VERSION 5.7 ;
  NOWIREEXTENSIONATPIN ON ;
  DIVIDERCHAR "/" ;
  BUSBITCHARS "[]" ;
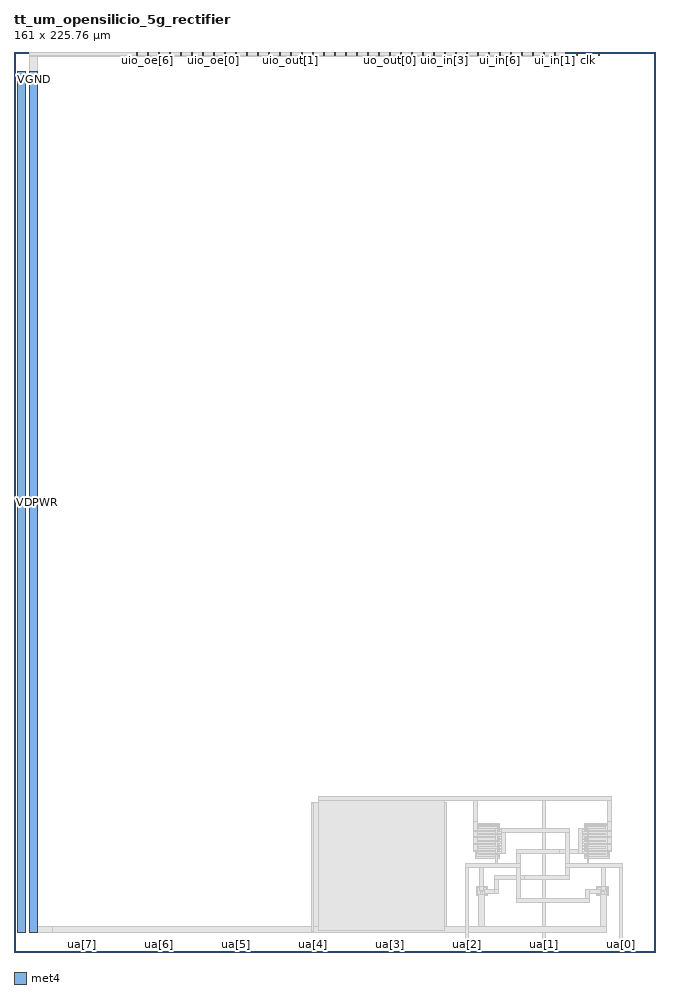
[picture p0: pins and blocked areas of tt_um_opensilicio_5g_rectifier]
MACRO tt_um_opensilicio_5g_rectifier
  CLASS BLOCK ;
  FOREIGN tt_um_opensilicio_5g_rectifier ;
  ORIGIN 0.000 0.000 ;
  SIZE 161.000 BY 225.760 ;
  PIN clk
    PORT
      LAYER met4 ;
        RECT 143.830 224.760 144.130 225.760 ;
    END
  END clk
  PIN ena
    PORT
      LAYER met4 ;
        RECT 146.590 224.760 146.890 225.760 ;
    END
  END ena
  PIN rst_n
    PORT
      LAYER met4 ;
        RECT 141.070 224.760 141.370 225.760 ;
    END
  END rst_n
  PIN ua[0]
    ANTENNAGATEAREA 11.349999 ;
    ANTENNADIFFAREA 8.700000 ;
    PORT
      LAYER met4 ;
        RECT 151.810 0.000 152.710 1.000 ;
    END
  END ua[0]
  PIN ua[1]
    ANTENNADIFFAREA 25.118799 ;
    PORT
      LAYER met4 ;
        RECT 132.490 0.000 133.390 1.000 ;
    END
  END ua[1]
  PIN ua[2]
    ANTENNAGATEAREA 11.349999 ;
    ANTENNADIFFAREA 8.700000 ;
    PORT
      LAYER met4 ;
        RECT 113.170 0.000 114.070 1.000 ;
    END
  END ua[2]
  PIN ua[3]
    PORT
      LAYER met4 ;
        RECT 93.850 0.000 94.750 1.000 ;
    END
  END ua[3]
  PIN ua[4]
    PORT
      LAYER met4 ;
        RECT 74.530 0.000 75.430 1.000 ;
    END
  END ua[4]
  PIN ua[5]
    PORT
      LAYER met4 ;
        RECT 55.210 0.000 56.110 1.000 ;
    END
  END ua[5]
  PIN ua[6]
    PORT
      LAYER met4 ;
        RECT 35.890 0.000 36.790 1.000 ;
    END
  END ua[6]
  PIN ua[7]
    PORT
      LAYER met4 ;
        RECT 16.570 0.000 17.470 1.000 ;
    END
  END ua[7]
  PIN ui_in[0]
    ANTENNADIFFAREA 3.496800 ;
    PORT
      LAYER met4 ;
        RECT 138.310 224.760 138.610 225.760 ;
    END
  END ui_in[0]
  PIN ui_in[1]
    ANTENNADIFFAREA 3.496800 ;
    PORT
      LAYER met4 ;
        RECT 135.550 224.760 135.850 225.760 ;
    END
  END ui_in[1]
  PIN ui_in[2]
    ANTENNADIFFAREA 3.496800 ;
    PORT
      LAYER met4 ;
        RECT 132.790 224.760 133.090 225.760 ;
    END
  END ui_in[2]
  PIN ui_in[3]
    ANTENNADIFFAREA 3.496800 ;
    PORT
      LAYER met4 ;
        RECT 130.030 224.760 130.330 225.760 ;
    END
  END ui_in[3]
  PIN ui_in[4]
    ANTENNADIFFAREA 3.496800 ;
    PORT
      LAYER met4 ;
        RECT 127.270 224.760 127.570 225.760 ;
    END
  END ui_in[4]
  PIN ui_in[5]
    ANTENNADIFFAREA 3.496800 ;
    PORT
      LAYER met4 ;
        RECT 124.510 224.760 124.810 225.760 ;
    END
  END ui_in[5]
  PIN ui_in[6]
    ANTENNADIFFAREA 3.496800 ;
    PORT
      LAYER met4 ;
        RECT 121.750 224.760 122.050 225.760 ;
    END
  END ui_in[6]
  PIN ui_in[7]
    ANTENNADIFFAREA 3.496800 ;
    PORT
      LAYER met4 ;
        RECT 118.990 224.760 119.290 225.760 ;
    END
  END ui_in[7]
  PIN uio_in[0]
    ANTENNADIFFAREA 3.496800 ;
    PORT
      LAYER met4 ;
        RECT 116.230 224.760 116.530 225.760 ;
    END
  END uio_in[0]
  PIN uio_in[1]
    ANTENNADIFFAREA 3.496800 ;
    PORT
      LAYER met4 ;
        RECT 113.470 224.760 113.770 225.760 ;
    END
  END uio_in[1]
  PIN uio_in[2]
    ANTENNADIFFAREA 3.496800 ;
    PORT
      LAYER met4 ;
        RECT 110.710 224.760 111.010 225.760 ;
    END
  END uio_in[2]
  PIN uio_in[3]
    ANTENNADIFFAREA 3.496800 ;
    PORT
      LAYER met4 ;
        RECT 107.950 224.760 108.250 225.760 ;
    END
  END uio_in[3]
  PIN uio_in[4]
    ANTENNADIFFAREA 3.496800 ;
    PORT
      LAYER met4 ;
        RECT 105.190 224.760 105.490 225.760 ;
    END
  END uio_in[4]
  PIN uio_in[5]
    ANTENNADIFFAREA 3.496800 ;
    PORT
      LAYER met4 ;
        RECT 102.430 224.760 102.730 225.760 ;
    END
  END uio_in[5]
  PIN uio_in[6]
    ANTENNADIFFAREA 3.496800 ;
    PORT
      LAYER met4 ;
        RECT 99.670 224.760 99.970 225.760 ;
    END
  END uio_in[6]
  PIN uio_in[7]
    ANTENNADIFFAREA 3.496800 ;
    PORT
      LAYER met4 ;
        RECT 96.910 224.760 97.210 225.760 ;
    END
  END uio_in[7]
  PIN uio_oe[0]
    ANTENNADIFFAREA 3.496800 ;
    PORT
      LAYER met4 ;
        RECT 49.990 224.760 50.290 225.760 ;
    END
  END uio_oe[0]
  PIN uio_oe[1]
    ANTENNADIFFAREA 3.496800 ;
    PORT
      LAYER met4 ;
        RECT 47.230 224.760 47.530 225.760 ;
    END
  END uio_oe[1]
  PIN uio_oe[2]
    ANTENNADIFFAREA 3.496800 ;
    PORT
      LAYER met4 ;
        RECT 44.470 224.760 44.770 225.760 ;
    END
  END uio_oe[2]
  PIN uio_oe[3]
    ANTENNADIFFAREA 3.496800 ;
    PORT
      LAYER met4 ;
        RECT 41.710 224.760 42.010 225.760 ;
    END
  END uio_oe[3]
  PIN uio_oe[4]
    ANTENNADIFFAREA 3.496800 ;
    PORT
      LAYER met4 ;
        RECT 38.950 224.760 39.250 225.760 ;
    END
  END uio_oe[4]
  PIN uio_oe[5]
    ANTENNADIFFAREA 3.496800 ;
    PORT
      LAYER met4 ;
        RECT 36.190 224.760 36.490 225.760 ;
    END
  END uio_oe[5]
  PIN uio_oe[6]
    ANTENNADIFFAREA 3.496800 ;
    PORT
      LAYER met4 ;
        RECT 33.430 224.760 33.730 225.760 ;
    END
  END uio_oe[6]
  PIN uio_oe[7]
    ANTENNADIFFAREA 3.496800 ;
    PORT
      LAYER met4 ;
        RECT 30.670 224.760 30.970 225.760 ;
    END
  END uio_oe[7]
  PIN uio_out[0]
    ANTENNADIFFAREA 3.496800 ;
    PORT
      LAYER met4 ;
        RECT 72.070 224.760 72.370 225.760 ;
    END
  END uio_out[0]
  PIN uio_out[1]
    ANTENNADIFFAREA 3.496800 ;
    PORT
      LAYER met4 ;
        RECT 69.310 224.760 69.610 225.760 ;
    END
  END uio_out[1]
  PIN uio_out[2]
    ANTENNADIFFAREA 3.496800 ;
    PORT
      LAYER met4 ;
        RECT 66.550 224.760 66.850 225.760 ;
    END
  END uio_out[2]
  PIN uio_out[3]
    ANTENNADIFFAREA 3.496800 ;
    PORT
      LAYER met4 ;
        RECT 63.790 224.760 64.090 225.760 ;
    END
  END uio_out[3]
  PIN uio_out[4]
    ANTENNADIFFAREA 3.496800 ;
    PORT
      LAYER met4 ;
        RECT 61.030 224.760 61.330 225.760 ;
    END
  END uio_out[4]
  PIN uio_out[5]
    ANTENNADIFFAREA 3.496800 ;
    PORT
      LAYER met4 ;
        RECT 58.270 224.760 58.570 225.760 ;
    END
  END uio_out[5]
  PIN uio_out[6]
    ANTENNADIFFAREA 3.496800 ;
    PORT
      LAYER met4 ;
        RECT 55.510 224.760 55.810 225.760 ;
    END
  END uio_out[6]
  PIN uio_out[7]
    ANTENNADIFFAREA 3.496800 ;
    PORT
      LAYER met4 ;
        RECT 52.750 224.760 53.050 225.760 ;
    END
  END uio_out[7]
  PIN uo_out[0]
    ANTENNADIFFAREA 3.496800 ;
    PORT
      LAYER met4 ;
        RECT 94.150 224.760 94.450 225.760 ;
    END
  END uo_out[0]
  PIN uo_out[1]
    ANTENNADIFFAREA 3.496800 ;
    PORT
      LAYER met4 ;
        RECT 91.390 224.760 91.690 225.760 ;
    END
  END uo_out[1]
  PIN uo_out[2]
    ANTENNADIFFAREA 3.496800 ;
    PORT
      LAYER met4 ;
        RECT 88.630 224.760 88.930 225.760 ;
    END
  END uo_out[2]
  PIN uo_out[3]
    ANTENNADIFFAREA 3.496800 ;
    PORT
      LAYER met4 ;
        RECT 85.870 224.760 86.170 225.760 ;
    END
  END uo_out[3]
  PIN uo_out[4]
    ANTENNADIFFAREA 3.496800 ;
    PORT
      LAYER met4 ;
        RECT 83.110 224.760 83.410 225.760 ;
    END
  END uo_out[4]
  PIN uo_out[5]
    ANTENNADIFFAREA 3.496800 ;
    PORT
      LAYER met4 ;
        RECT 80.350 224.760 80.650 225.760 ;
    END
  END uo_out[5]
  PIN uo_out[6]
    ANTENNADIFFAREA 3.496800 ;
    PORT
      LAYER met4 ;
        RECT 77.590 224.760 77.890 225.760 ;
    END
  END uo_out[6]
  PIN uo_out[7]
    ANTENNADIFFAREA 3.496800 ;
    PORT
      LAYER met4 ;
        RECT 74.830 224.760 75.130 225.760 ;
    END
  END uo_out[7]
  PIN VDPWR
    USE POWER ;
    PORT
      LAYER met4 ;
        RECT 1.000 5.000 3.000 220.760 ;
    END
  END VDPWR
  PIN VGND
    USE GROUND ;
    PORT
      LAYER met4 ;
        RECT 4.000 5.000 6.000 220.760 ;
    END
  END VGND
  OBS
      LAYER nwell ;
        RECT 115.660 23.535 121.890 32.275 ;
        RECT 143.135 23.535 149.365 32.275 ;
      LAYER pwell ;
        RECT 115.975 14.150 118.855 16.390 ;
        RECT 146.170 14.150 149.050 16.390 ;
      LAYER li1 ;
        RECT 115.965 31.800 121.585 31.970 ;
        RECT 115.965 30.810 116.135 31.800 ;
        RECT 116.640 31.120 120.570 31.290 ;
        RECT 115.935 24.810 116.185 30.810 ;
        RECT 120.885 30.715 121.055 31.045 ;
        RECT 116.640 30.370 120.570 30.540 ;
        RECT 120.885 29.865 121.055 30.195 ;
        RECT 116.640 29.520 120.570 29.690 ;
        RECT 120.885 29.015 121.055 29.345 ;
        RECT 116.640 28.670 120.570 28.840 ;
        RECT 120.885 28.165 121.055 28.495 ;
        RECT 116.640 27.820 120.570 27.990 ;
        RECT 120.885 27.315 121.055 27.645 ;
        RECT 116.640 26.970 120.570 27.140 ;
        RECT 120.885 26.465 121.055 26.795 ;
        RECT 116.640 26.120 120.570 26.290 ;
        RECT 120.885 25.615 121.055 25.945 ;
        RECT 116.640 25.270 120.570 25.440 ;
        RECT 115.965 24.010 116.135 24.810 ;
        RECT 120.885 24.765 121.055 25.095 ;
        RECT 116.640 24.520 120.570 24.690 ;
        RECT 121.415 24.010 121.585 31.800 ;
        RECT 115.965 23.840 121.585 24.010 ;
        RECT 143.440 31.800 149.060 31.970 ;
        RECT 143.440 24.010 143.610 31.800 ;
        RECT 144.455 31.120 148.385 31.290 ;
        RECT 143.970 30.715 144.140 31.045 ;
        RECT 148.890 30.810 149.060 31.800 ;
        RECT 144.455 30.370 148.385 30.540 ;
        RECT 143.970 29.865 144.140 30.195 ;
        RECT 144.455 29.520 148.385 29.690 ;
        RECT 143.970 29.015 144.140 29.345 ;
        RECT 144.455 28.670 148.385 28.840 ;
        RECT 143.970 28.165 144.140 28.495 ;
        RECT 144.455 27.820 148.385 27.990 ;
        RECT 143.970 27.315 144.140 27.645 ;
        RECT 144.455 26.970 148.385 27.140 ;
        RECT 143.970 26.465 144.140 26.795 ;
        RECT 144.455 26.120 148.385 26.290 ;
        RECT 143.970 25.615 144.140 25.945 ;
        RECT 144.455 25.270 148.385 25.440 ;
        RECT 143.970 24.765 144.140 25.095 ;
        RECT 148.840 24.810 149.090 30.810 ;
        RECT 144.455 24.520 148.385 24.690 ;
        RECT 148.890 24.010 149.060 24.810 ;
        RECT 143.440 23.840 149.060 24.010 ;
        RECT 116.105 16.090 118.725 16.260 ;
        RECT 116.105 14.450 116.275 16.090 ;
        RECT 116.900 15.410 117.590 15.580 ;
        RECT 116.900 14.960 117.590 15.130 ;
        RECT 118.025 15.105 118.195 15.435 ;
        RECT 116.500 14.450 118.000 14.515 ;
        RECT 118.555 14.450 118.725 16.090 ;
        RECT 116.105 14.280 118.725 14.450 ;
        RECT 146.300 16.090 148.920 16.260 ;
        RECT 146.300 14.450 146.470 16.090 ;
        RECT 146.830 15.105 147.000 15.435 ;
        RECT 147.435 15.410 148.125 15.580 ;
        RECT 147.435 14.960 148.125 15.130 ;
        RECT 147.025 14.450 148.525 14.515 ;
        RECT 148.750 14.450 148.920 16.090 ;
        RECT 146.300 14.280 148.920 14.450 ;
        RECT 116.500 14.185 118.000 14.280 ;
        RECT 147.025 14.185 148.525 14.280 ;
      LAYER met1 ;
        RECT 115.300 30.570 116.300 38.990 ;
        RECT 116.605 31.050 120.605 31.370 ;
        RECT 120.855 30.695 123.355 31.065 ;
        RECT 115.300 30.340 120.550 30.570 ;
        RECT 115.300 28.870 116.300 30.340 ;
        RECT 122.355 30.215 123.355 30.695 ;
        RECT 120.855 29.845 123.355 30.215 ;
        RECT 116.605 29.445 120.605 29.765 ;
        RECT 122.355 29.365 123.355 29.845 ;
        RECT 120.855 28.995 123.355 29.365 ;
        RECT 115.300 28.640 120.550 28.870 ;
        RECT 115.300 27.170 116.300 28.640 ;
        RECT 122.355 28.515 123.355 28.995 ;
        RECT 120.855 28.145 123.355 28.515 ;
        RECT 116.605 27.745 120.605 28.065 ;
        RECT 122.355 27.665 123.355 28.145 ;
        RECT 120.855 27.295 123.355 27.665 ;
        RECT 115.300 26.940 120.550 27.170 ;
        RECT 115.300 25.470 116.300 26.940 ;
        RECT 122.355 26.815 123.355 27.295 ;
        RECT 120.855 26.445 123.355 26.815 ;
        RECT 116.605 26.045 120.605 26.365 ;
        RECT 122.355 25.965 123.355 26.445 ;
        RECT 120.855 25.595 123.355 25.965 ;
        RECT 115.300 25.240 120.550 25.470 ;
        RECT 115.935 24.810 116.185 25.240 ;
        RECT 122.355 25.115 123.355 25.595 ;
        RECT 116.605 24.445 120.605 24.765 ;
        RECT 120.855 24.745 123.355 25.115 ;
        RECT 141.670 30.695 144.170 31.065 ;
        RECT 144.420 31.050 148.420 31.370 ;
        RECT 141.670 30.215 142.670 30.695 ;
        RECT 148.800 30.570 149.800 38.990 ;
        RECT 144.475 30.340 149.800 30.570 ;
        RECT 141.670 29.845 144.170 30.215 ;
        RECT 141.670 29.365 142.670 29.845 ;
        RECT 144.420 29.445 148.420 29.765 ;
        RECT 141.670 28.995 144.170 29.365 ;
        RECT 141.670 28.515 142.670 28.995 ;
        RECT 148.800 28.870 149.800 30.340 ;
        RECT 144.475 28.640 149.800 28.870 ;
        RECT 141.670 28.145 144.170 28.515 ;
        RECT 141.670 27.665 142.670 28.145 ;
        RECT 144.420 27.745 148.420 28.065 ;
        RECT 141.670 27.295 144.170 27.665 ;
        RECT 141.670 26.815 142.670 27.295 ;
        RECT 148.800 27.170 149.800 28.640 ;
        RECT 144.475 26.940 149.800 27.170 ;
        RECT 141.670 26.445 144.170 26.815 ;
        RECT 141.670 25.965 142.670 26.445 ;
        RECT 144.420 26.045 148.420 26.365 ;
        RECT 141.670 25.595 144.170 25.965 ;
        RECT 141.670 25.115 142.670 25.595 ;
        RECT 148.800 25.470 149.800 26.940 ;
        RECT 144.475 25.240 149.800 25.470 ;
        RECT 141.670 24.745 144.170 25.115 ;
        RECT 148.840 24.810 149.090 25.240 ;
        RECT 144.420 24.445 148.420 24.765 ;
        RECT 116.745 15.380 117.745 17.495 ;
        RECT 116.920 14.515 117.570 15.160 ;
        RECT 117.995 14.770 121.560 15.770 ;
        RECT 143.465 14.770 147.030 15.770 ;
        RECT 147.280 15.380 148.280 17.495 ;
        RECT 147.455 14.515 148.105 15.160 ;
        RECT 116.500 14.185 118.000 14.515 ;
        RECT 147.025 14.185 148.525 14.515 ;
      LAYER met2 ;
        RECT 115.300 32.690 116.300 38.990 ;
        RECT 130.050 37.990 136.050 38.990 ;
        RECT 116.605 31.050 121.290 31.370 ;
        RECT 120.855 29.765 121.290 31.050 ;
        RECT 116.605 29.445 121.290 29.765 ;
        RECT 120.855 28.065 121.290 29.445 ;
        RECT 116.605 27.745 121.290 28.065 ;
        RECT 120.855 26.365 121.290 27.745 ;
        RECT 116.605 26.045 121.290 26.365 ;
        RECT 120.855 24.765 121.290 26.045 ;
        RECT 116.605 24.445 121.290 24.765 ;
        RECT 122.355 24.745 123.355 31.065 ;
        RECT 120.855 22.210 121.290 24.445 ;
        RECT 115.660 21.210 121.860 22.210 ;
        RECT 116.745 16.495 117.745 17.495 ;
        RECT 120.560 14.770 121.560 15.770 ;
        RECT 116.500 14.185 118.000 14.515 ;
        RECT 132.490 1.280 133.390 37.990 ;
        RECT 148.800 32.690 149.800 38.990 ;
        RECT 141.670 24.765 142.670 31.065 ;
        RECT 143.735 31.050 148.420 31.370 ;
        RECT 143.735 29.765 144.170 31.050 ;
        RECT 143.735 29.445 148.420 29.765 ;
        RECT 143.735 28.065 144.170 29.445 ;
        RECT 143.735 27.745 148.420 28.065 ;
        RECT 143.735 26.365 144.170 27.745 ;
        RECT 143.735 26.045 148.420 26.365 ;
        RECT 143.735 24.765 144.170 26.045 ;
        RECT 143.735 24.445 148.420 24.765 ;
        RECT 143.735 22.210 144.170 24.445 ;
        RECT 143.165 21.210 149.365 22.210 ;
        RECT 147.280 16.495 148.280 17.495 ;
        RECT 143.465 14.770 144.465 15.770 ;
        RECT 147.025 14.185 148.525 14.515 ;
      LAYER met3 ;
        RECT 74.635 6.295 108.495 37.400 ;
        RECT 115.300 32.690 116.300 38.990 ;
        RECT 130.050 37.990 136.050 38.990 ;
        RECT 148.800 32.690 149.800 38.990 ;
        RECT 122.355 24.745 123.355 31.065 ;
        RECT 141.670 25.745 142.670 31.065 ;
        RECT 133.835 24.745 142.670 25.745 ;
        RECT 115.660 21.210 121.860 22.210 ;
        RECT 143.165 21.210 149.365 22.210 ;
        RECT 120.560 18.210 131.145 19.210 ;
        RECT 116.745 16.495 117.745 17.495 ;
        RECT 120.560 14.770 121.560 18.210 ;
        RECT 147.280 16.495 148.280 17.495 ;
        RECT 143.465 14.770 144.465 15.770 ;
        RECT 116.500 6.295 118.000 14.515 ;
        RECT 147.025 6.295 148.525 14.515 ;
        RECT 6.720 5.000 148.525 6.295 ;
        RECT 132.490 1.280 133.390 3.280 ;
      LAYER met4 ;
        RECT 4.000 224.760 30.670 225.510 ;
        RECT 30.970 224.760 33.430 225.510 ;
        RECT 33.730 224.760 36.190 225.510 ;
        RECT 36.490 224.760 38.950 225.510 ;
        RECT 39.250 224.760 41.710 225.510 ;
        RECT 42.010 224.760 44.470 225.510 ;
        RECT 44.770 224.760 47.230 225.510 ;
        RECT 47.530 224.760 49.990 225.510 ;
        RECT 50.290 224.760 52.750 225.510 ;
        RECT 53.050 224.760 55.510 225.510 ;
        RECT 55.810 224.760 58.270 225.510 ;
        RECT 58.570 224.760 61.030 225.510 ;
        RECT 61.330 224.760 63.790 225.510 ;
        RECT 64.090 224.760 66.550 225.510 ;
        RECT 66.850 224.760 69.310 225.510 ;
        RECT 69.610 224.760 72.070 225.510 ;
        RECT 72.370 224.760 74.830 225.510 ;
        RECT 75.130 224.760 77.590 225.510 ;
        RECT 77.890 224.760 80.350 225.510 ;
        RECT 80.650 224.760 83.110 225.510 ;
        RECT 83.410 224.760 85.870 225.510 ;
        RECT 86.170 224.760 88.630 225.510 ;
        RECT 88.930 224.760 91.390 225.510 ;
        RECT 91.690 224.760 94.150 225.510 ;
        RECT 94.450 224.760 96.910 225.510 ;
        RECT 97.210 224.760 99.670 225.510 ;
        RECT 99.970 224.760 102.430 225.510 ;
        RECT 102.730 224.760 105.190 225.510 ;
        RECT 105.490 224.760 107.950 225.510 ;
        RECT 108.250 224.760 110.710 225.510 ;
        RECT 111.010 224.760 113.470 225.510 ;
        RECT 113.770 224.760 116.230 225.510 ;
        RECT 116.530 224.760 118.990 225.510 ;
        RECT 119.290 224.760 121.750 225.510 ;
        RECT 122.050 224.760 124.510 225.510 ;
        RECT 124.810 224.760 127.270 225.510 ;
        RECT 127.570 224.760 130.030 225.510 ;
        RECT 130.330 224.760 132.790 225.510 ;
        RECT 133.090 224.760 135.550 225.510 ;
        RECT 135.850 224.760 138.310 225.510 ;
        RECT 4.000 224.510 138.610 224.760 ;
        RECT 4.000 220.760 6.000 224.510 ;
        RECT 76.490 37.990 149.800 38.990 ;
        RECT 6.000 5.000 9.720 6.295 ;
        RECT 74.655 5.060 75.135 37.340 ;
        RECT 76.490 5.395 108.100 37.990 ;
        RECT 115.300 32.690 116.300 37.990 ;
        RECT 148.800 32.690 149.800 37.990 ;
        RECT 122.355 30.065 139.325 31.065 ;
        RECT 122.355 24.745 123.355 30.065 ;
        RECT 126.095 24.745 136.835 25.745 ;
        RECT 126.095 22.210 127.095 24.745 ;
        RECT 113.170 21.210 127.095 22.210 ;
        RECT 113.170 1.000 114.070 21.210 ;
        RECT 116.745 16.495 117.745 21.210 ;
        RECT 120.560 14.770 121.560 15.770 ;
        RECT 126.095 13.330 127.095 21.210 ;
        RECT 138.325 22.210 139.325 30.065 ;
        RECT 141.670 24.765 142.670 31.065 ;
        RECT 138.325 21.210 152.710 22.210 ;
        RECT 138.325 19.210 139.325 21.210 ;
        RECT 128.145 18.210 139.325 19.210 ;
        RECT 147.280 16.495 148.280 21.210 ;
        RECT 143.465 13.330 144.465 15.770 ;
        RECT 126.095 12.330 144.465 13.330 ;
        RECT 132.490 1.000 133.390 3.280 ;
        RECT 151.810 1.000 152.710 21.210 ;
  END
END tt_um_opensilicio_5g_rectifier
END LIBRARY

